VERSION 5.7 ;
  NOWIREEXTENSIONATPIN ON ;
  DIVIDERCHAR "/" ;
  BUSBITCHARS "[]" ;
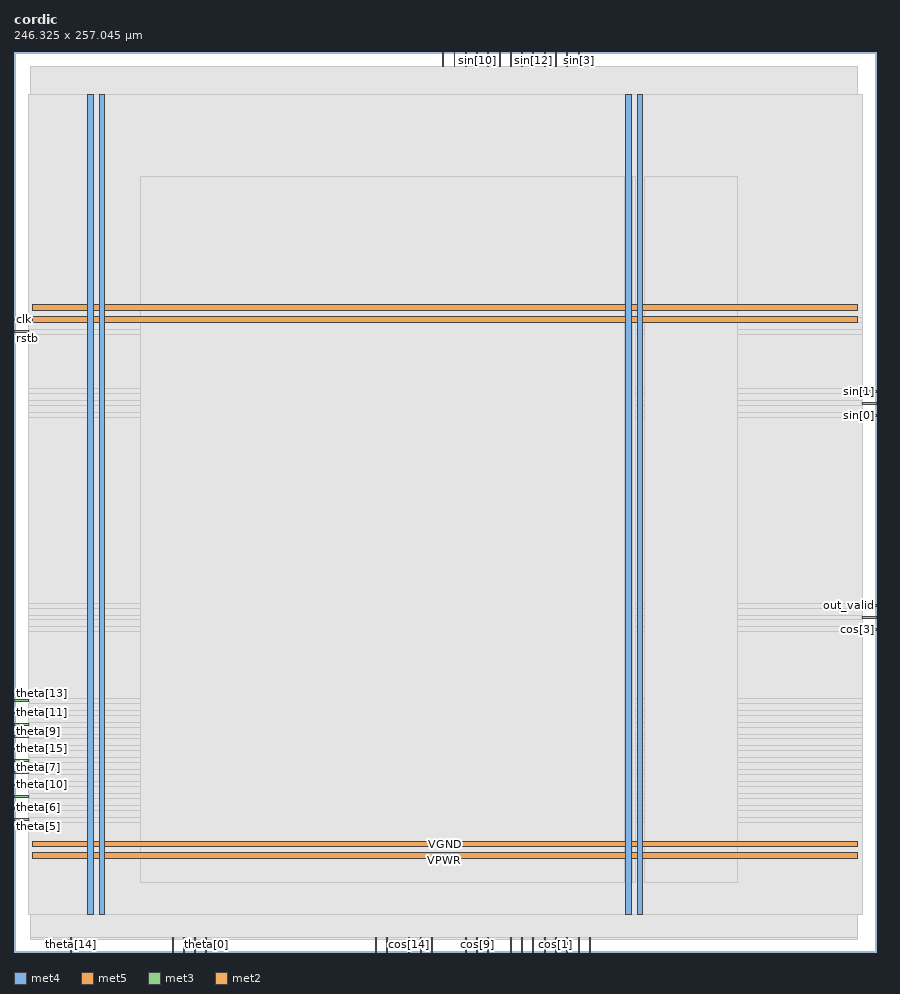
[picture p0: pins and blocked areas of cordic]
MACRO cordic
  CLASS BLOCK ;
  FOREIGN cordic ;
  ORIGIN 0.000 0.000 ;
  SIZE 246.325 BY 257.045 ;
  PIN VGND
    DIRECTION INOUT ;
    USE GROUND ;
    PORT
      LAYER met4 ;
        RECT 24.340 10.640 25.940 245.040 ;
    END
    PORT
      LAYER met4 ;
        RECT 177.940 10.640 179.540 245.040 ;
    END
    PORT
      LAYER met5 ;
        RECT 5.280 30.030 240.820 31.630 ;
    END
    PORT
      LAYER met5 ;
        RECT 5.280 183.210 240.820 184.810 ;
    END
  END VGND
  PIN VPWR
    DIRECTION INOUT ;
    USE POWER ;
    PORT
      LAYER met4 ;
        RECT 21.040 10.640 22.640 245.040 ;
    END
    PORT
      LAYER met4 ;
        RECT 174.640 10.640 176.240 245.040 ;
    END
    PORT
      LAYER met5 ;
        RECT 5.280 26.730 240.820 28.330 ;
    END
    PORT
      LAYER met5 ;
        RECT 5.280 179.910 240.820 181.510 ;
    END
  END VPWR
  PIN clk
    DIRECTION INPUT ;
    USE SIGNAL ;
    ANTENNAGATEAREA 0.852000 ;
    PORT
      LAYER met3 ;
        RECT 0.000 180.240 4.000 180.840 ;
    END
  END clk
  PIN cos[0]
    DIRECTION OUTPUT ;
    USE SIGNAL ;
    ANTENNADIFFAREA 0.445500 ;
    PORT
      LAYER met3 ;
        RECT 242.325 95.240 246.325 95.840 ;
    END
  END cos[0]
  PIN cos[10]
    DIRECTION OUTPUT ;
    USE SIGNAL ;
    ANTENNADIFFAREA 0.795200 ;
    PORT
      LAYER met2 ;
        RECT 128.890 0.000 129.170 4.000 ;
    END
  END cos[10]
  PIN cos[11]
    DIRECTION OUTPUT ;
    USE SIGNAL ;
    ANTENNADIFFAREA 0.795200 ;
    PORT
      LAYER met2 ;
        RECT 135.330 0.000 135.610 4.000 ;
    END
  END cos[11]
  PIN cos[12]
    DIRECTION OUTPUT ;
    USE SIGNAL ;
    ANTENNADIFFAREA 0.795200 ;
    PORT
      LAYER met2 ;
        RECT 106.350 0.000 106.630 4.000 ;
    END
  END cos[12]
  PIN cos[13]
    DIRECTION OUTPUT ;
    USE SIGNAL ;
    ANTENNADIFFAREA 0.795200 ;
    PORT
      LAYER met2 ;
        RECT 103.130 0.000 103.410 4.000 ;
    END
  END cos[13]
  PIN cos[14]
    DIRECTION OUTPUT ;
    USE SIGNAL ;
    ANTENNADIFFAREA 0.795200 ;
    PORT
      LAYER met2 ;
        RECT 112.790 0.000 113.070 4.000 ;
    END
  END cos[14]
  PIN cos[15]
    DIRECTION OUTPUT ;
    USE SIGNAL ;
    ANTENNADIFFAREA 0.795200 ;
    PORT
      LAYER met2 ;
        RECT 119.230 0.000 119.510 4.000 ;
    END
  END cos[15]
  PIN cos[1]
    DIRECTION OUTPUT ;
    USE SIGNAL ;
    ANTENNADIFFAREA 0.795200 ;
    PORT
      LAYER met2 ;
        RECT 154.650 0.000 154.930 4.000 ;
    END
  END cos[1]
  PIN cos[2]
    DIRECTION OUTPUT ;
    USE SIGNAL ;
    ANTENNADIFFAREA 0.795200 ;
    PORT
      LAYER met2 ;
        RECT 164.310 0.000 164.590 4.000 ;
    END
  END cos[2]
  PIN cos[3]
    DIRECTION OUTPUT ;
    USE SIGNAL ;
    ANTENNADIFFAREA 0.445500 ;
    PORT
      LAYER met3 ;
        RECT 242.325 91.840 246.325 92.440 ;
    END
  END cos[3]
  PIN cos[4]
    DIRECTION OUTPUT ;
    USE SIGNAL ;
    ANTENNADIFFAREA 0.795200 ;
    PORT
      LAYER met2 ;
        RECT 157.870 0.000 158.150 4.000 ;
    END
  END cos[4]
  PIN cos[5]
    DIRECTION OUTPUT ;
    USE SIGNAL ;
    ANTENNADIFFAREA 0.795200 ;
    PORT
      LAYER met2 ;
        RECT 161.090 0.000 161.370 4.000 ;
    END
  END cos[5]
  PIN cos[6]
    DIRECTION OUTPUT ;
    USE SIGNAL ;
    ANTENNADIFFAREA 0.795200 ;
    PORT
      LAYER met2 ;
        RECT 144.990 0.000 145.270 4.000 ;
    END
  END cos[6]
  PIN cos[7]
    DIRECTION OUTPUT ;
    USE SIGNAL ;
    ANTENNADIFFAREA 0.795200 ;
    PORT
      LAYER met2 ;
        RECT 148.210 0.000 148.490 4.000 ;
    END
  END cos[7]
  PIN cos[8]
    DIRECTION OUTPUT ;
    USE SIGNAL ;
    ANTENNADIFFAREA 0.795200 ;
    PORT
      LAYER met2 ;
        RECT 141.770 0.000 142.050 4.000 ;
    END
  END cos[8]
  PIN cos[9]
    DIRECTION OUTPUT ;
    USE SIGNAL ;
    ANTENNADIFFAREA 0.795200 ;
    PORT
      LAYER met2 ;
        RECT 132.110 0.000 132.390 4.000 ;
    END
  END cos[9]
  PIN in_valid
    DIRECTION INPUT ;
    USE SIGNAL ;
    ANTENNAGATEAREA 0.213000 ;
    PORT
      LAYER met2 ;
        RECT 116.010 0.000 116.290 4.000 ;
    END
  END in_valid
  PIN out_valid
    DIRECTION OUTPUT ;
    USE SIGNAL ;
    ANTENNADIFFAREA 0.445500 ;
    PORT
      LAYER met3 ;
        RECT 242.325 98.640 246.325 99.240 ;
    END
  END out_valid
  PIN ready
    DIRECTION OUTPUT ;
    USE SIGNAL ;
    ANTENNADIFFAREA 0.795200 ;
    PORT
      LAYER met2 ;
        RECT 151.430 0.000 151.710 4.000 ;
    END
  END ready
  PIN rstb
    DIRECTION INPUT ;
    USE SIGNAL ;
    ANTENNAGATEAREA 0.196500 ;
    PORT
      LAYER met3 ;
        RECT 0.000 176.840 4.000 177.440 ;
    END
  END rstb
  PIN sin[0]
    DIRECTION OUTPUT ;
    USE SIGNAL ;
    ANTENNADIFFAREA 0.445500 ;
    PORT
      LAYER met3 ;
        RECT 242.325 153.040 246.325 153.640 ;
    END
  END sin[0]
  PIN sin[10]
    DIRECTION OUTPUT ;
    USE SIGNAL ;
    ANTENNADIFFAREA 0.795200 ;
    PORT
      LAYER met2 ;
        RECT 132.110 253.045 132.390 257.045 ;
    END
  END sin[10]
  PIN sin[11]
    DIRECTION OUTPUT ;
    USE SIGNAL ;
    ANTENNADIFFAREA 0.795200 ;
    PORT
      LAYER met2 ;
        RECT 128.890 253.045 129.170 257.045 ;
    END
  END sin[11]
  PIN sin[12]
    DIRECTION OUTPUT ;
    USE SIGNAL ;
    ANTENNADIFFAREA 0.795200 ;
    PORT
      LAYER met2 ;
        RECT 148.210 253.045 148.490 257.045 ;
    END
  END sin[12]
  PIN sin[13]
    DIRECTION OUTPUT ;
    USE SIGNAL ;
    ANTENNADIFFAREA 0.795200 ;
    PORT
      LAYER met2 ;
        RECT 144.990 253.045 145.270 257.045 ;
    END
  END sin[13]
  PIN sin[14]
    DIRECTION OUTPUT ;
    USE SIGNAL ;
    ANTENNADIFFAREA 0.795200 ;
    PORT
      LAYER met2 ;
        RECT 135.330 253.045 135.610 257.045 ;
    END
  END sin[14]
  PIN sin[15]
    DIRECTION OUTPUT ;
    USE SIGNAL ;
    ANTENNADIFFAREA 0.795200 ;
    PORT
      LAYER met2 ;
        RECT 125.670 253.045 125.950 257.045 ;
    END
  END sin[15]
  PIN sin[1]
    DIRECTION OUTPUT ;
    USE SIGNAL ;
    ANTENNADIFFAREA 0.445500 ;
    PORT
      LAYER met3 ;
        RECT 242.325 159.840 246.325 160.440 ;
    END
  END sin[1]
  PIN sin[2]
    DIRECTION OUTPUT ;
    USE SIGNAL ;
    ANTENNADIFFAREA 0.795200 ;
    PORT
      LAYER met3 ;
        RECT 242.325 156.440 246.325 157.040 ;
    END
  END sin[2]
  PIN sin[3]
    DIRECTION OUTPUT ;
    USE SIGNAL ;
    ANTENNADIFFAREA 0.795200 ;
    PORT
      LAYER met2 ;
        RECT 161.090 253.045 161.370 257.045 ;
    END
  END sin[3]
  PIN sin[4]
    DIRECTION OUTPUT ;
    USE SIGNAL ;
    ANTENNADIFFAREA 0.445500 ;
    PORT
      LAYER met2 ;
        RECT 154.650 253.045 154.930 257.045 ;
    END
  END sin[4]
  PIN sin[5]
    DIRECTION OUTPUT ;
    USE SIGNAL ;
    ANTENNADIFFAREA 0.795200 ;
    PORT
      LAYER met2 ;
        RECT 157.870 253.045 158.150 257.045 ;
    END
  END sin[5]
  PIN sin[6]
    DIRECTION OUTPUT ;
    USE SIGNAL ;
    ANTENNADIFFAREA 0.795200 ;
    PORT
      LAYER met2 ;
        RECT 141.770 253.045 142.050 257.045 ;
    END
  END sin[6]
  PIN sin[7]
    DIRECTION OUTPUT ;
    USE SIGNAL ;
    ANTENNADIFFAREA 0.795200 ;
    PORT
      LAYER met2 ;
        RECT 151.430 253.045 151.710 257.045 ;
    END
  END sin[7]
  PIN sin[8]
    DIRECTION OUTPUT ;
    USE SIGNAL ;
    ANTENNADIFFAREA 0.795200 ;
    PORT
      LAYER met2 ;
        RECT 138.550 253.045 138.830 257.045 ;
    END
  END sin[8]
  PIN sin[9]
    DIRECTION OUTPUT ;
    USE SIGNAL ;
    ANTENNADIFFAREA 0.795200 ;
    PORT
      LAYER met2 ;
        RECT 122.450 253.045 122.730 257.045 ;
    END
  END sin[9]
  PIN theta[0]
    DIRECTION INPUT ;
    USE SIGNAL ;
    ANTENNAGATEAREA 0.126000 ;
    PORT
      LAYER met2 ;
        RECT 54.830 0.000 55.110 4.000 ;
    END
  END theta[0]
  PIN theta[10]
    DIRECTION INPUT ;
    USE SIGNAL ;
    ANTENNAGATEAREA 0.196500 ;
    PORT
      LAYER met3 ;
        RECT 0.000 47.640 4.000 48.240 ;
    END
  END theta[10]
  PIN theta[11]
    DIRECTION INPUT ;
    USE SIGNAL ;
    ANTENNAGATEAREA 0.196500 ;
    PORT
      LAYER met3 ;
        RECT 0.000 68.040 4.000 68.640 ;
    END
  END theta[11]
  PIN theta[12]
    DIRECTION INPUT ;
    USE SIGNAL ;
    ANTENNAGATEAREA 0.196500 ;
    PORT
      LAYER met3 ;
        RECT 0.000 61.240 4.000 61.840 ;
    END
  END theta[12]
  PIN theta[13]
    DIRECTION INPUT ;
    USE SIGNAL ;
    ANTENNAGATEAREA 0.196500 ;
    PORT
      LAYER met3 ;
        RECT 0.000 71.440 4.000 72.040 ;
    END
  END theta[13]
  PIN theta[14]
    DIRECTION INPUT ;
    USE SIGNAL ;
    ANTENNAGATEAREA 0.196500 ;
    PORT
      LAYER met2 ;
        RECT 16.190 0.000 16.470 4.000 ;
    END
  END theta[14]
  PIN theta[15]
    DIRECTION INPUT ;
    USE SIGNAL ;
    ANTENNAGATEAREA 0.159000 ;
    PORT
      LAYER met3 ;
        RECT 0.000 57.840 4.000 58.440 ;
    END
  END theta[15]
  PIN theta[1]
    DIRECTION INPUT ;
    USE SIGNAL ;
    ANTENNAGATEAREA 0.196500 ;
    PORT
      LAYER met2 ;
        RECT 51.610 0.000 51.890 4.000 ;
    END
  END theta[1]
  PIN theta[2]
    DIRECTION INPUT ;
    USE SIGNAL ;
    ANTENNAGATEAREA 0.196500 ;
    PORT
      LAYER met2 ;
        RECT 48.390 0.000 48.670 4.000 ;
    END
  END theta[2]
  PIN theta[3]
    DIRECTION INPUT ;
    USE SIGNAL ;
    ANTENNAGATEAREA 0.196500 ;
    PORT
      LAYER met2 ;
        RECT 45.170 0.000 45.450 4.000 ;
    END
  END theta[3]
  PIN theta[4]
    DIRECTION INPUT ;
    USE SIGNAL ;
    ANTENNAGATEAREA 0.196500 ;
    PORT
      LAYER met3 ;
        RECT 0.000 44.240 4.000 44.840 ;
    END
  END theta[4]
  PIN theta[5]
    DIRECTION INPUT ;
    USE SIGNAL ;
    ANTENNAGATEAREA 0.196500 ;
    PORT
      LAYER met3 ;
        RECT 0.000 37.440 4.000 38.040 ;
    END
  END theta[5]
  PIN theta[6]
    DIRECTION INPUT ;
    USE SIGNAL ;
    ANTENNAGATEAREA 0.196500 ;
    PORT
      LAYER met3 ;
        RECT 0.000 40.840 4.000 41.440 ;
    END
  END theta[6]
  PIN theta[7]
    DIRECTION INPUT ;
    USE SIGNAL ;
    ANTENNAGATEAREA 0.196500 ;
    PORT
      LAYER met3 ;
        RECT 0.000 54.440 4.000 55.040 ;
    END
  END theta[7]
  PIN theta[8]
    DIRECTION INPUT ;
    USE SIGNAL ;
    ANTENNAGATEAREA 0.196500 ;
    PORT
      LAYER met3 ;
        RECT 0.000 51.040 4.000 51.640 ;
    END
  END theta[8]
  PIN theta[9]
    DIRECTION INPUT ;
    USE SIGNAL ;
    ANTENNAGATEAREA 0.196500 ;
    PORT
      LAYER met3 ;
        RECT 0.000 64.640 4.000 65.240 ;
    END
  END theta[9]
  OBS
      LAYER li1 ;
        RECT 5.520 10.795 240.580 244.885 ;
      LAYER met1 ;
        RECT 4.670 7.520 240.970 245.040 ;
      LAYER met2 ;
        RECT 4.690 252.765 122.170 253.045 ;
        RECT 123.010 252.765 125.390 253.045 ;
        RECT 126.230 252.765 128.610 253.045 ;
        RECT 129.450 252.765 131.830 253.045 ;
        RECT 132.670 252.765 135.050 253.045 ;
        RECT 135.890 252.765 138.270 253.045 ;
        RECT 139.110 252.765 141.490 253.045 ;
        RECT 142.330 252.765 144.710 253.045 ;
        RECT 145.550 252.765 147.930 253.045 ;
        RECT 148.770 252.765 151.150 253.045 ;
        RECT 151.990 252.765 154.370 253.045 ;
        RECT 155.210 252.765 157.590 253.045 ;
        RECT 158.430 252.765 160.810 253.045 ;
        RECT 161.650 252.765 240.950 253.045 ;
        RECT 4.690 4.280 240.950 252.765 ;
        RECT 4.690 3.670 15.910 4.280 ;
        RECT 16.750 3.670 44.890 4.280 ;
        RECT 45.730 3.670 48.110 4.280 ;
        RECT 48.950 3.670 51.330 4.280 ;
        RECT 52.170 3.670 54.550 4.280 ;
        RECT 55.390 3.670 102.850 4.280 ;
        RECT 103.690 3.670 106.070 4.280 ;
        RECT 106.910 3.670 112.510 4.280 ;
        RECT 113.350 3.670 115.730 4.280 ;
        RECT 116.570 3.670 118.950 4.280 ;
        RECT 119.790 3.670 128.610 4.280 ;
        RECT 129.450 3.670 131.830 4.280 ;
        RECT 132.670 3.670 135.050 4.280 ;
        RECT 135.890 3.670 141.490 4.280 ;
        RECT 142.330 3.670 144.710 4.280 ;
        RECT 145.550 3.670 147.930 4.280 ;
        RECT 148.770 3.670 151.150 4.280 ;
        RECT 151.990 3.670 154.370 4.280 ;
        RECT 155.210 3.670 157.590 4.280 ;
        RECT 158.430 3.670 160.810 4.280 ;
        RECT 161.650 3.670 164.030 4.280 ;
        RECT 164.870 3.670 240.950 4.280 ;
      LAYER met3 ;
        RECT 4.000 181.240 242.325 244.965 ;
        RECT 4.400 179.840 242.325 181.240 ;
        RECT 4.000 177.840 242.325 179.840 ;
        RECT 4.400 176.440 242.325 177.840 ;
        RECT 4.000 160.840 242.325 176.440 ;
        RECT 4.000 159.440 241.925 160.840 ;
        RECT 4.000 157.440 242.325 159.440 ;
        RECT 4.000 156.040 241.925 157.440 ;
        RECT 4.000 154.040 242.325 156.040 ;
        RECT 4.000 152.640 241.925 154.040 ;
        RECT 4.000 99.640 242.325 152.640 ;
        RECT 4.000 98.240 241.925 99.640 ;
        RECT 4.000 96.240 242.325 98.240 ;
        RECT 4.000 94.840 241.925 96.240 ;
        RECT 4.000 92.840 242.325 94.840 ;
        RECT 4.000 91.440 241.925 92.840 ;
        RECT 4.000 72.440 242.325 91.440 ;
        RECT 4.400 71.040 242.325 72.440 ;
        RECT 4.000 69.040 242.325 71.040 ;
        RECT 4.400 67.640 242.325 69.040 ;
        RECT 4.000 65.640 242.325 67.640 ;
        RECT 4.400 64.240 242.325 65.640 ;
        RECT 4.000 62.240 242.325 64.240 ;
        RECT 4.400 60.840 242.325 62.240 ;
        RECT 4.000 58.840 242.325 60.840 ;
        RECT 4.400 57.440 242.325 58.840 ;
        RECT 4.000 55.440 242.325 57.440 ;
        RECT 4.400 54.040 242.325 55.440 ;
        RECT 4.000 52.040 242.325 54.040 ;
        RECT 4.400 50.640 242.325 52.040 ;
        RECT 4.000 48.640 242.325 50.640 ;
        RECT 4.400 47.240 242.325 48.640 ;
        RECT 4.000 45.240 242.325 47.240 ;
        RECT 4.400 43.840 242.325 45.240 ;
        RECT 4.000 41.840 242.325 43.840 ;
        RECT 4.400 40.440 242.325 41.840 ;
        RECT 4.000 38.440 242.325 40.440 ;
        RECT 4.400 37.040 242.325 38.440 ;
        RECT 4.000 10.715 242.325 37.040 ;
      LAYER met4 ;
        RECT 36.175 19.895 174.240 221.505 ;
        RECT 176.640 19.895 177.540 221.505 ;
        RECT 179.940 19.895 206.705 221.505 ;
  END
END cordic
END LIBRARY

